VERSION 5.7 ;
  NOWIREEXTENSIONATPIN ON ;
  DIVIDERCHAR "/" ;
  BUSBITCHARS "[]" ;
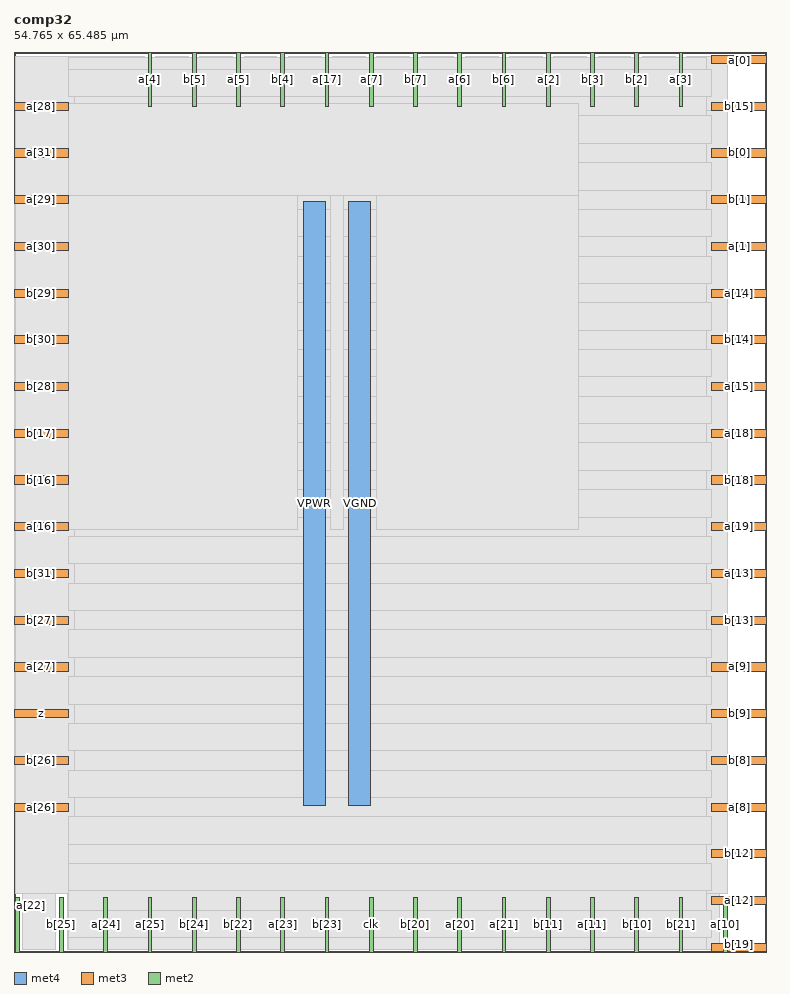
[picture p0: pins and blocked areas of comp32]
MACRO comp32
  CLASS BLOCK ;
  FOREIGN comp32 ;
  ORIGIN 0.000 0.000 ;
  SIZE 54.765 BY 65.485 ;
  PIN VGND
    DIRECTION INOUT ;
    USE GROUND ;
    PORT
      LAYER met4 ;
        RECT 24.340 10.640 25.940 54.640 ;
    END
  END VGND
  PIN VPWR
    DIRECTION INOUT ;
    USE POWER ;
    PORT
      LAYER met4 ;
        RECT 21.040 10.640 22.640 54.640 ;
    END
  END VPWR
  PIN a[0]
    DIRECTION INPUT ;
    USE SIGNAL ;
    ANTENNAGATEAREA 0.196500 ;
    PORT
      LAYER met3 ;
        RECT 50.765 64.640 54.765 65.240 ;
    END
  END a[0]
  PIN a[10]
    DIRECTION INPUT ;
    USE SIGNAL ;
    ANTENNAGATEAREA 0.196500 ;
    PORT
      LAYER met2 ;
        RECT 51.610 0.000 51.890 4.000 ;
    END
  END a[10]
  PIN a[11]
    DIRECTION INPUT ;
    USE SIGNAL ;
    ANTENNAGATEAREA 0.196500 ;
    PORT
      LAYER met2 ;
        RECT 41.950 0.000 42.230 4.000 ;
    END
  END a[11]
  PIN a[12]
    DIRECTION INPUT ;
    USE SIGNAL ;
    ANTENNAGATEAREA 0.196500 ;
    PORT
      LAYER met3 ;
        RECT 50.765 3.440 54.765 4.040 ;
    END
  END a[12]
  PIN a[13]
    DIRECTION INPUT ;
    USE SIGNAL ;
    ANTENNAGATEAREA 0.196500 ;
    PORT
      LAYER met3 ;
        RECT 50.765 27.240 54.765 27.840 ;
    END
  END a[13]
  PIN a[14]
    DIRECTION INPUT ;
    USE SIGNAL ;
    ANTENNAGATEAREA 0.196500 ;
    PORT
      LAYER met3 ;
        RECT 50.765 47.640 54.765 48.240 ;
    END
  END a[14]
  PIN a[15]
    DIRECTION INPUT ;
    USE SIGNAL ;
    ANTENNAGATEAREA 0.196500 ;
    PORT
      LAYER met3 ;
        RECT 50.765 40.840 54.765 41.440 ;
    END
  END a[15]
  PIN a[16]
    DIRECTION INPUT ;
    USE SIGNAL ;
    ANTENNAGATEAREA 0.196500 ;
    PORT
      LAYER met3 ;
        RECT 0.000 30.640 4.000 31.240 ;
    END
  END a[16]
  PIN a[17]
    DIRECTION INPUT ;
    USE SIGNAL ;
    ANTENNAGATEAREA 0.196500 ;
    PORT
      LAYER met2 ;
        RECT 22.630 61.485 22.910 65.485 ;
    END
  END a[17]
  PIN a[18]
    DIRECTION INPUT ;
    USE SIGNAL ;
    ANTENNAGATEAREA 0.196500 ;
    PORT
      LAYER met3 ;
        RECT 50.765 37.440 54.765 38.040 ;
    END
  END a[18]
  PIN a[19]
    DIRECTION INPUT ;
    USE SIGNAL ;
    ANTENNAGATEAREA 0.196500 ;
    PORT
      LAYER met3 ;
        RECT 50.765 30.640 54.765 31.240 ;
    END
  END a[19]
  PIN a[1]
    DIRECTION INPUT ;
    USE SIGNAL ;
    ANTENNAGATEAREA 0.196500 ;
    PORT
      LAYER met3 ;
        RECT 50.765 51.040 54.765 51.640 ;
    END
  END a[1]
  PIN a[20]
    DIRECTION INPUT ;
    USE SIGNAL ;
    ANTENNAGATEAREA 0.196500 ;
    PORT
      LAYER met2 ;
        RECT 32.290 0.000 32.570 4.000 ;
    END
  END a[20]
  PIN a[21]
    DIRECTION INPUT ;
    USE SIGNAL ;
    ANTENNAGATEAREA 0.196500 ;
    PORT
      LAYER met2 ;
        RECT 35.510 0.000 35.790 4.000 ;
    END
  END a[21]
  PIN a[22]
    DIRECTION INPUT ;
    USE SIGNAL ;
    ANTENNAGATEAREA 0.196500 ;
    PORT
      LAYER met2 ;
        RECT 0.090 0.000 0.370 4.000 ;
    END
  END a[22]
  PIN a[23]
    DIRECTION INPUT ;
    USE SIGNAL ;
    ANTENNAGATEAREA 0.196500 ;
    PORT
      LAYER met2 ;
        RECT 19.410 0.000 19.690 4.000 ;
    END
  END a[23]
  PIN a[24]
    DIRECTION INPUT ;
    USE SIGNAL ;
    ANTENNAGATEAREA 0.196500 ;
    PORT
      LAYER met2 ;
        RECT 6.530 0.000 6.810 4.000 ;
    END
  END a[24]
  PIN a[25]
    DIRECTION INPUT ;
    USE SIGNAL ;
    ANTENNAGATEAREA 0.196500 ;
    PORT
      LAYER met2 ;
        RECT 9.750 0.000 10.030 4.000 ;
    END
  END a[25]
  PIN a[26]
    DIRECTION INPUT ;
    USE SIGNAL ;
    ANTENNAGATEAREA 0.196500 ;
    PORT
      LAYER met3 ;
        RECT 0.000 10.240 4.000 10.840 ;
    END
  END a[26]
  PIN a[27]
    DIRECTION INPUT ;
    USE SIGNAL ;
    ANTENNAGATEAREA 0.196500 ;
    PORT
      LAYER met3 ;
        RECT 0.000 20.440 4.000 21.040 ;
    END
  END a[27]
  PIN a[28]
    DIRECTION INPUT ;
    USE SIGNAL ;
    ANTENNAGATEAREA 0.196500 ;
    PORT
      LAYER met3 ;
        RECT 0.000 61.240 4.000 61.840 ;
    END
  END a[28]
  PIN a[29]
    DIRECTION INPUT ;
    USE SIGNAL ;
    ANTENNAGATEAREA 0.196500 ;
    PORT
      LAYER met3 ;
        RECT 0.000 54.440 4.000 55.040 ;
    END
  END a[29]
  PIN a[2]
    DIRECTION INPUT ;
    USE SIGNAL ;
    ANTENNAGATEAREA 0.196500 ;
    PORT
      LAYER met2 ;
        RECT 38.730 61.485 39.010 65.485 ;
    END
  END a[2]
  PIN a[30]
    DIRECTION INPUT ;
    USE SIGNAL ;
    ANTENNAGATEAREA 0.495000 ;
    PORT
      LAYER met3 ;
        RECT 0.000 51.040 4.000 51.640 ;
    END
  END a[30]
  PIN a[31]
    DIRECTION INPUT ;
    USE SIGNAL ;
    ANTENNAGATEAREA 0.196500 ;
    PORT
      LAYER met3 ;
        RECT 0.000 57.840 4.000 58.440 ;
    END
  END a[31]
  PIN a[3]
    DIRECTION INPUT ;
    USE SIGNAL ;
    ANTENNAGATEAREA 0.196500 ;
    PORT
      LAYER met2 ;
        RECT 48.390 61.485 48.670 65.485 ;
    END
  END a[3]
  PIN a[4]
    DIRECTION INPUT ;
    USE SIGNAL ;
    ANTENNAGATEAREA 0.196500 ;
    PORT
      LAYER met2 ;
        RECT 9.750 61.485 10.030 65.485 ;
    END
  END a[4]
  PIN a[5]
    DIRECTION INPUT ;
    USE SIGNAL ;
    ANTENNAGATEAREA 0.196500 ;
    PORT
      LAYER met2 ;
        RECT 16.190 61.485 16.470 65.485 ;
    END
  END a[5]
  PIN a[6]
    DIRECTION INPUT ;
    USE SIGNAL ;
    ANTENNAGATEAREA 0.196500 ;
    PORT
      LAYER met2 ;
        RECT 32.290 61.485 32.570 65.485 ;
    END
  END a[6]
  PIN a[7]
    DIRECTION INPUT ;
    USE SIGNAL ;
    ANTENNAGATEAREA 0.196500 ;
    PORT
      LAYER met2 ;
        RECT 25.850 61.485 26.130 65.485 ;
    END
  END a[7]
  PIN a[8]
    DIRECTION INPUT ;
    USE SIGNAL ;
    ANTENNAGATEAREA 0.196500 ;
    PORT
      LAYER met3 ;
        RECT 50.765 10.240 54.765 10.840 ;
    END
  END a[8]
  PIN a[9]
    DIRECTION INPUT ;
    USE SIGNAL ;
    ANTENNAGATEAREA 0.196500 ;
    PORT
      LAYER met3 ;
        RECT 50.765 20.440 54.765 21.040 ;
    END
  END a[9]
  PIN b[0]
    DIRECTION INPUT ;
    USE SIGNAL ;
    ANTENNAGATEAREA 0.196500 ;
    PORT
      LAYER met3 ;
        RECT 50.765 57.840 54.765 58.440 ;
    END
  END b[0]
  PIN b[10]
    DIRECTION INPUT ;
    USE SIGNAL ;
    ANTENNAGATEAREA 0.196500 ;
    PORT
      LAYER met2 ;
        RECT 45.170 0.000 45.450 4.000 ;
    END
  END b[10]
  PIN b[11]
    DIRECTION INPUT ;
    USE SIGNAL ;
    ANTENNAGATEAREA 0.196500 ;
    PORT
      LAYER met2 ;
        RECT 38.730 0.000 39.010 4.000 ;
    END
  END b[11]
  PIN b[12]
    DIRECTION INPUT ;
    USE SIGNAL ;
    ANTENNAGATEAREA 0.196500 ;
    PORT
      LAYER met3 ;
        RECT 50.765 6.840 54.765 7.440 ;
    END
  END b[12]
  PIN b[13]
    DIRECTION INPUT ;
    USE SIGNAL ;
    ANTENNAGATEAREA 0.196500 ;
    PORT
      LAYER met3 ;
        RECT 50.765 23.840 54.765 24.440 ;
    END
  END b[13]
  PIN b[14]
    DIRECTION INPUT ;
    USE SIGNAL ;
    ANTENNAGATEAREA 0.196500 ;
    PORT
      LAYER met3 ;
        RECT 50.765 44.240 54.765 44.840 ;
    END
  END b[14]
  PIN b[15]
    DIRECTION INPUT ;
    USE SIGNAL ;
    ANTENNAGATEAREA 0.196500 ;
    PORT
      LAYER met3 ;
        RECT 50.765 61.240 54.765 61.840 ;
    END
  END b[15]
  PIN b[16]
    DIRECTION INPUT ;
    USE SIGNAL ;
    ANTENNAGATEAREA 0.196500 ;
    PORT
      LAYER met3 ;
        RECT 0.000 34.040 4.000 34.640 ;
    END
  END b[16]
  PIN b[17]
    DIRECTION INPUT ;
    USE SIGNAL ;
    ANTENNAGATEAREA 0.196500 ;
    PORT
      LAYER met3 ;
        RECT 0.000 37.440 4.000 38.040 ;
    END
  END b[17]
  PIN b[18]
    DIRECTION INPUT ;
    USE SIGNAL ;
    ANTENNAGATEAREA 0.196500 ;
    PORT
      LAYER met3 ;
        RECT 50.765 34.040 54.765 34.640 ;
    END
  END b[18]
  PIN b[19]
    DIRECTION INPUT ;
    USE SIGNAL ;
    ANTENNAGATEAREA 0.196500 ;
    PORT
      LAYER met3 ;
        RECT 50.765 0.040 54.765 0.640 ;
    END
  END b[19]
  PIN b[1]
    DIRECTION INPUT ;
    USE SIGNAL ;
    ANTENNAGATEAREA 0.196500 ;
    PORT
      LAYER met3 ;
        RECT 50.765 54.440 54.765 55.040 ;
    END
  END b[1]
  PIN b[20]
    DIRECTION INPUT ;
    USE SIGNAL ;
    ANTENNAGATEAREA 0.196500 ;
    PORT
      LAYER met2 ;
        RECT 29.070 0.000 29.350 4.000 ;
    END
  END b[20]
  PIN b[21]
    DIRECTION INPUT ;
    USE SIGNAL ;
    ANTENNAGATEAREA 0.196500 ;
    PORT
      LAYER met2 ;
        RECT 48.390 0.000 48.670 4.000 ;
    END
  END b[21]
  PIN b[22]
    DIRECTION INPUT ;
    USE SIGNAL ;
    ANTENNAGATEAREA 0.196500 ;
    PORT
      LAYER met2 ;
        RECT 16.190 0.000 16.470 4.000 ;
    END
  END b[22]
  PIN b[23]
    DIRECTION INPUT ;
    USE SIGNAL ;
    ANTENNAGATEAREA 0.196500 ;
    PORT
      LAYER met2 ;
        RECT 22.630 0.000 22.910 4.000 ;
    END
  END b[23]
  PIN b[24]
    DIRECTION INPUT ;
    USE SIGNAL ;
    ANTENNAGATEAREA 0.196500 ;
    PORT
      LAYER met2 ;
        RECT 12.970 0.000 13.250 4.000 ;
    END
  END b[24]
  PIN b[25]
    DIRECTION INPUT ;
    USE SIGNAL ;
    ANTENNAGATEAREA 0.196500 ;
    PORT
      LAYER met2 ;
        RECT 3.310 0.000 3.590 4.000 ;
    END
  END b[25]
  PIN b[26]
    DIRECTION INPUT ;
    USE SIGNAL ;
    ANTENNAGATEAREA 0.196500 ;
    PORT
      LAYER met3 ;
        RECT 0.000 13.640 4.000 14.240 ;
    END
  END b[26]
  PIN b[27]
    DIRECTION INPUT ;
    USE SIGNAL ;
    ANTENNAGATEAREA 0.196500 ;
    PORT
      LAYER met3 ;
        RECT 0.000 23.840 4.000 24.440 ;
    END
  END b[27]
  PIN b[28]
    DIRECTION INPUT ;
    USE SIGNAL ;
    ANTENNAGATEAREA 0.196500 ;
    PORT
      LAYER met3 ;
        RECT 0.000 40.840 4.000 41.440 ;
    END
  END b[28]
  PIN b[29]
    DIRECTION INPUT ;
    USE SIGNAL ;
    ANTENNAGATEAREA 0.196500 ;
    PORT
      LAYER met3 ;
        RECT 0.000 47.640 4.000 48.240 ;
    END
  END b[29]
  PIN b[2]
    DIRECTION INPUT ;
    USE SIGNAL ;
    ANTENNAGATEAREA 0.196500 ;
    PORT
      LAYER met2 ;
        RECT 45.170 61.485 45.450 65.485 ;
    END
  END b[2]
  PIN b[30]
    DIRECTION INPUT ;
    USE SIGNAL ;
    ANTENNAGATEAREA 0.196500 ;
    PORT
      LAYER met3 ;
        RECT 0.000 44.240 4.000 44.840 ;
    END
  END b[30]
  PIN b[31]
    DIRECTION INPUT ;
    USE SIGNAL ;
    ANTENNAGATEAREA 0.196500 ;
    PORT
      LAYER met3 ;
        RECT 0.000 27.240 4.000 27.840 ;
    END
  END b[31]
  PIN b[3]
    DIRECTION INPUT ;
    USE SIGNAL ;
    ANTENNAGATEAREA 0.196500 ;
    PORT
      LAYER met2 ;
        RECT 41.950 61.485 42.230 65.485 ;
    END
  END b[3]
  PIN b[4]
    DIRECTION INPUT ;
    USE SIGNAL ;
    ANTENNAGATEAREA 0.196500 ;
    PORT
      LAYER met2 ;
        RECT 19.410 61.485 19.690 65.485 ;
    END
  END b[4]
  PIN b[5]
    DIRECTION INPUT ;
    USE SIGNAL ;
    ANTENNAGATEAREA 0.196500 ;
    PORT
      LAYER met2 ;
        RECT 12.970 61.485 13.250 65.485 ;
    END
  END b[5]
  PIN b[6]
    DIRECTION INPUT ;
    USE SIGNAL ;
    ANTENNAGATEAREA 0.196500 ;
    PORT
      LAYER met2 ;
        RECT 35.510 61.485 35.790 65.485 ;
    END
  END b[6]
  PIN b[7]
    DIRECTION INPUT ;
    USE SIGNAL ;
    ANTENNAGATEAREA 0.196500 ;
    PORT
      LAYER met2 ;
        RECT 29.070 61.485 29.350 65.485 ;
    END
  END b[7]
  PIN b[8]
    DIRECTION INPUT ;
    USE SIGNAL ;
    ANTENNAGATEAREA 0.196500 ;
    PORT
      LAYER met3 ;
        RECT 50.765 13.640 54.765 14.240 ;
    END
  END b[8]
  PIN b[9]
    DIRECTION INPUT ;
    USE SIGNAL ;
    ANTENNAGATEAREA 0.196500 ;
    PORT
      LAYER met3 ;
        RECT 50.765 17.040 54.765 17.640 ;
    END
  END b[9]
  PIN clk
    DIRECTION INPUT ;
    USE SIGNAL ;
    ANTENNAGATEAREA 0.159000 ;
    PORT
      LAYER met2 ;
        RECT 25.850 0.000 26.130 4.000 ;
    END
  END clk
  PIN z
    DIRECTION OUTPUT ;
    USE SIGNAL ;
    ANTENNADIFFAREA 0.445500 ;
    PORT
      LAYER met3 ;
        RECT 0.000 17.040 4.000 17.640 ;
    END
  END z
  OBS
      LAYER li1 ;
        RECT 5.520 10.795 49.220 54.485 ;
      LAYER met1 ;
        RECT 0.070 10.640 51.910 54.640 ;
      LAYER met2 ;
        RECT 0.100 61.205 9.470 65.125 ;
        RECT 10.310 61.205 12.690 65.125 ;
        RECT 13.530 61.205 15.910 65.125 ;
        RECT 16.750 61.205 19.130 65.125 ;
        RECT 19.970 61.205 22.350 65.125 ;
        RECT 23.190 61.205 25.570 65.125 ;
        RECT 26.410 61.205 28.790 65.125 ;
        RECT 29.630 61.205 32.010 65.125 ;
        RECT 32.850 61.205 35.230 65.125 ;
        RECT 36.070 61.205 38.450 65.125 ;
        RECT 39.290 61.205 41.670 65.125 ;
        RECT 42.510 61.205 44.890 65.125 ;
        RECT 45.730 61.205 48.110 65.125 ;
        RECT 48.950 61.205 51.880 65.125 ;
        RECT 0.100 4.280 51.880 61.205 ;
        RECT 0.650 0.155 3.030 4.280 ;
        RECT 3.870 0.155 6.250 4.280 ;
        RECT 7.090 0.155 9.470 4.280 ;
        RECT 10.310 0.155 12.690 4.280 ;
        RECT 13.530 0.155 15.910 4.280 ;
        RECT 16.750 0.155 19.130 4.280 ;
        RECT 19.970 0.155 22.350 4.280 ;
        RECT 23.190 0.155 25.570 4.280 ;
        RECT 26.410 0.155 28.790 4.280 ;
        RECT 29.630 0.155 32.010 4.280 ;
        RECT 32.850 0.155 35.230 4.280 ;
        RECT 36.070 0.155 38.450 4.280 ;
        RECT 39.290 0.155 41.670 4.280 ;
        RECT 42.510 0.155 44.890 4.280 ;
        RECT 45.730 0.155 48.110 4.280 ;
        RECT 48.950 0.155 51.330 4.280 ;
      LAYER met3 ;
        RECT 3.950 64.240 50.365 65.105 ;
        RECT 3.950 62.240 50.765 64.240 ;
        RECT 4.400 60.840 50.365 62.240 ;
        RECT 3.950 58.840 50.765 60.840 ;
        RECT 4.400 57.440 50.365 58.840 ;
        RECT 3.950 55.440 50.765 57.440 ;
        RECT 4.400 54.040 50.365 55.440 ;
        RECT 3.950 52.040 50.765 54.040 ;
        RECT 4.400 50.640 50.365 52.040 ;
        RECT 3.950 48.640 50.765 50.640 ;
        RECT 4.400 47.240 50.365 48.640 ;
        RECT 3.950 45.240 50.765 47.240 ;
        RECT 4.400 43.840 50.365 45.240 ;
        RECT 3.950 41.840 50.765 43.840 ;
        RECT 4.400 40.440 50.365 41.840 ;
        RECT 3.950 38.440 50.765 40.440 ;
        RECT 4.400 37.040 50.365 38.440 ;
        RECT 3.950 35.040 50.765 37.040 ;
        RECT 4.400 33.640 50.365 35.040 ;
        RECT 3.950 31.640 50.765 33.640 ;
        RECT 4.400 30.240 50.365 31.640 ;
        RECT 3.950 28.240 50.765 30.240 ;
        RECT 4.400 26.840 50.365 28.240 ;
        RECT 3.950 24.840 50.765 26.840 ;
        RECT 4.400 23.440 50.365 24.840 ;
        RECT 3.950 21.440 50.765 23.440 ;
        RECT 4.400 20.040 50.365 21.440 ;
        RECT 3.950 18.040 50.765 20.040 ;
        RECT 4.400 16.640 50.365 18.040 ;
        RECT 3.950 14.640 50.765 16.640 ;
        RECT 4.400 13.240 50.365 14.640 ;
        RECT 3.950 11.240 50.765 13.240 ;
        RECT 4.400 9.840 50.365 11.240 ;
        RECT 3.950 7.840 50.765 9.840 ;
        RECT 3.950 6.440 50.365 7.840 ;
        RECT 3.950 4.440 50.765 6.440 ;
        RECT 3.950 3.040 50.365 4.440 ;
        RECT 3.950 1.040 50.765 3.040 ;
        RECT 3.950 0.175 50.365 1.040 ;
      LAYER met4 ;
        RECT 3.975 55.040 41.105 61.705 ;
        RECT 3.975 30.775 20.640 55.040 ;
        RECT 23.040 30.775 23.940 55.040 ;
        RECT 26.340 30.775 41.105 55.040 ;
  END
END comp32
END LIBRARY

